One B-rep face of a CAD part: STEP entity #796.
In plain terms, the planar face has unit normal (0, -0.995, 0.104).
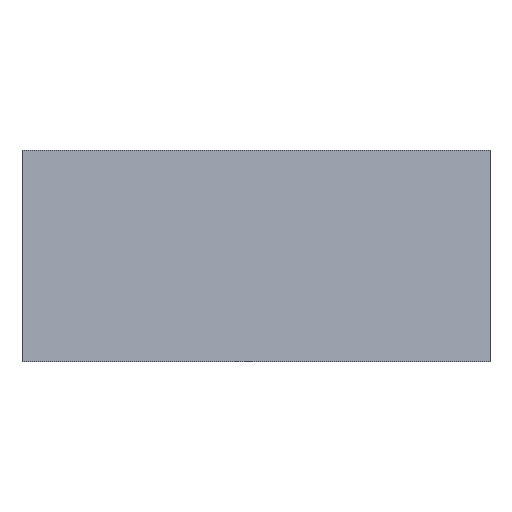
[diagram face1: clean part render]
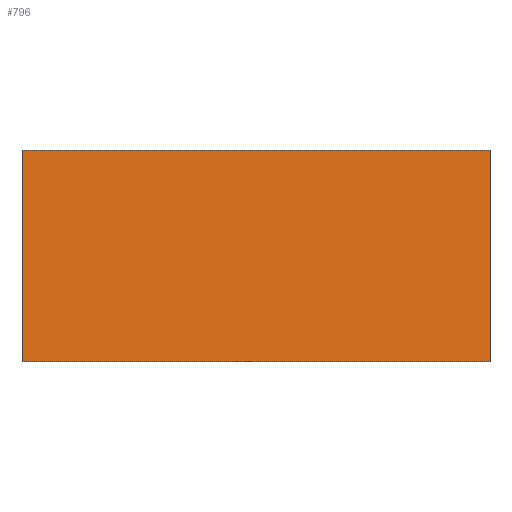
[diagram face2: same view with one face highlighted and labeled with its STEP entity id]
Its self-contained STEP definition (entity closure, numbers rounded to 3 decimals):
#32 = PLANE('',#33);
#33 = AXIS2_PLACEMENT_3D('',#34,#35,#36);
#34 = CARTESIAN_POINT('',(-29.,0.557,-11.5));
#35 = DIRECTION('',(1.,-0.,-0.));
#36 = DIRECTION('',(0.,0.,-1.));
#169 = VERTEX_POINT('',#170);
#170 = CARTESIAN_POINT('',(-29.,-1.524,-20.833));
#184 = PLANE('',#185);
#185 = AXIS2_PLACEMENT_3D('',#186,#187,#188);
#186 = CARTESIAN_POINT('',(-400.,388.,-20.833));
#187 = DIRECTION('',(0.,0.,1.));
#188 = DIRECTION('',(-1.,-0.,0.));
#196 = EDGE_CURVE('',#169,#197,#199,.T.);
#197 = VERTEX_POINT('',#198);
#198 = CARTESIAN_POINT('',(-29.,0.665,0.));
#199 = SURFACE_CURVE('',#200,(#204,#211),.PCURVE_S1.);
#200 = LINE('',#201,#202);
#201 = CARTESIAN_POINT('',(-29.,-4.59,-50.));
#202 = VECTOR('',#203,1.);
#203 = DIRECTION('',(-0.,0.105,0.995));
#204 = PCURVE('',#32,#205);
#205 = DEFINITIONAL_REPRESENTATION('',(#206),#210);
#206 = LINE('',#207,#208);
#207 = CARTESIAN_POINT('',(38.5,-5.147));
#208 = VECTOR('',#209,1.);
#209 = DIRECTION('',(-0.995,0.105));
#210 = ( GEOMETRIC_REPRESENTATION_CONTEXT(2) 
PARAMETRIC_REPRESENTATION_CONTEXT() REPRESENTATION_CONTEXT('2D SPACE',''
  ) );
#211 = PCURVE('',#212,#217);
#212 = PLANE('',#213);
#213 = AXIS2_PLACEMENT_3D('',#214,#215,#216);
#214 = CARTESIAN_POINT('',(-29.,-4.59,-50.));
#215 = DIRECTION('',(0.,0.995,-0.105));
#216 = DIRECTION('',(0.,-0.105,-0.995));
#217 = DEFINITIONAL_REPRESENTATION('',(#218),#222);
#218 = LINE('',#219,#220);
#219 = CARTESIAN_POINT('',(-0.,0.));
#220 = VECTOR('',#221,1.);
#221 = DIRECTION('',(-1.,0.));
#222 = ( GEOMETRIC_REPRESENTATION_CONTEXT(2) 
PARAMETRIC_REPRESENTATION_CONTEXT() REPRESENTATION_CONTEXT('2D SPACE',''
  ) );
#240 = PLANE('',#241);
#241 = AXIS2_PLACEMENT_3D('',#242,#243,#244);
#242 = CARTESIAN_POINT('',(-400.,388.,0.));
#243 = DIRECTION('',(0.,0.,1.));
#244 = DIRECTION('',(-1.,-0.,0.));
#519 = PLANE('',#520);
#520 = AXIS2_PLACEMENT_3D('',#521,#522,#523);
#521 = CARTESIAN_POINT('',(17.,0.557,-11.5));
#522 = DIRECTION('',(1.,-0.,-0.));
#523 = DIRECTION('',(0.,0.,-1.));
#751 = EDGE_CURVE('',#752,#197,#754,.T.);
#752 = VERTEX_POINT('',#753);
#753 = CARTESIAN_POINT('',(17.,0.665,0.));
#754 = SURFACE_CURVE('',#755,(#759,#766),.PCURVE_S1.);
#755 = LINE('',#756,#757);
#756 = CARTESIAN_POINT('',(-214.5,0.665,0.));
#757 = VECTOR('',#758,1.);
#758 = DIRECTION('',(-1.,-0.,0.));
#759 = PCURVE('',#240,#760);
#760 = DEFINITIONAL_REPRESENTATION('',(#761),#765);
#761 = LINE('',#762,#763);
#762 = CARTESIAN_POINT('',(-185.5,387.335));
#763 = VECTOR('',#764,1.);
#764 = DIRECTION('',(1.,-0.));
#765 = ( GEOMETRIC_REPRESENTATION_CONTEXT(2) 
PARAMETRIC_REPRESENTATION_CONTEXT() REPRESENTATION_CONTEXT('2D SPACE',''
  ) );
#766 = PCURVE('',#212,#767);
#767 = DEFINITIONAL_REPRESENTATION('',(#768),#772);
#768 = LINE('',#769,#770);
#769 = CARTESIAN_POINT('',(-50.275,185.5));
#770 = VECTOR('',#771,1.);
#771 = DIRECTION('',(-0.,1.));
#772 = ( GEOMETRIC_REPRESENTATION_CONTEXT(2) 
PARAMETRIC_REPRESENTATION_CONTEXT() REPRESENTATION_CONTEXT('2D SPACE',''
  ) );
#796 = ADVANCED_FACE('',(#797),#212,.F.);
#797 = FACE_BOUND('',#798,.T.);
#798 = EDGE_LOOP('',(#799,#800,#823,#844));
#799 = ORIENTED_EDGE('',*,*,#196,.F.);
#800 = ORIENTED_EDGE('',*,*,#801,.F.);
#801 = EDGE_CURVE('',#802,#169,#804,.T.);
#802 = VERTEX_POINT('',#803);
#803 = CARTESIAN_POINT('',(17.,-1.524,-20.833));
#804 = SURFACE_CURVE('',#805,(#809,#816),.PCURVE_S1.);
#805 = LINE('',#806,#807);
#806 = CARTESIAN_POINT('',(-214.5,-1.524,-20.833));
#807 = VECTOR('',#808,1.);
#808 = DIRECTION('',(-1.,-0.,0.));
#809 = PCURVE('',#212,#810);
#810 = DEFINITIONAL_REPRESENTATION('',(#811),#815);
#811 = LINE('',#812,#813);
#812 = CARTESIAN_POINT('',(-29.327,185.5));
#813 = VECTOR('',#814,1.);
#814 = DIRECTION('',(-0.,1.));
#815 = ( GEOMETRIC_REPRESENTATION_CONTEXT(2) 
PARAMETRIC_REPRESENTATION_CONTEXT() REPRESENTATION_CONTEXT('2D SPACE',''
  ) );
#816 = PCURVE('',#184,#817);
#817 = DEFINITIONAL_REPRESENTATION('',(#818),#822);
#818 = LINE('',#819,#820);
#819 = CARTESIAN_POINT('',(-185.5,389.524));
#820 = VECTOR('',#821,1.);
#821 = DIRECTION('',(1.,-0.));
#822 = ( GEOMETRIC_REPRESENTATION_CONTEXT(2) 
PARAMETRIC_REPRESENTATION_CONTEXT() REPRESENTATION_CONTEXT('2D SPACE',''
  ) );
#823 = ORIENTED_EDGE('',*,*,#824,.T.);
#824 = EDGE_CURVE('',#802,#752,#825,.T.);
#825 = SURFACE_CURVE('',#826,(#830,#837),.PCURVE_S1.);
#826 = LINE('',#827,#828);
#827 = CARTESIAN_POINT('',(17.,-4.59,-50.));
#828 = VECTOR('',#829,1.);
#829 = DIRECTION('',(-0.,0.105,0.995));
#830 = PCURVE('',#212,#831);
#831 = DEFINITIONAL_REPRESENTATION('',(#832),#836);
#832 = LINE('',#833,#834);
#833 = CARTESIAN_POINT('',(-0.,-46.));
#834 = VECTOR('',#835,1.);
#835 = DIRECTION('',(-1.,0.));
#836 = ( GEOMETRIC_REPRESENTATION_CONTEXT(2) 
PARAMETRIC_REPRESENTATION_CONTEXT() REPRESENTATION_CONTEXT('2D SPACE',''
  ) );
#837 = PCURVE('',#519,#838);
#838 = DEFINITIONAL_REPRESENTATION('',(#839),#843);
#839 = LINE('',#840,#841);
#840 = CARTESIAN_POINT('',(38.5,-5.147));
#841 = VECTOR('',#842,1.);
#842 = DIRECTION('',(-0.995,0.105));
#843 = ( GEOMETRIC_REPRESENTATION_CONTEXT(2) 
PARAMETRIC_REPRESENTATION_CONTEXT() REPRESENTATION_CONTEXT('2D SPACE',''
  ) );
#844 = ORIENTED_EDGE('',*,*,#751,.T.);
